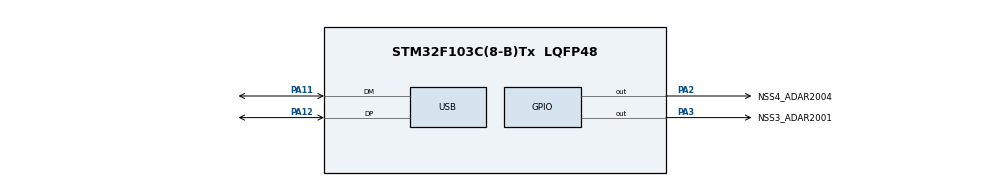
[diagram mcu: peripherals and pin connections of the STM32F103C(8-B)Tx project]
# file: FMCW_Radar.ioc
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Mcu.Family=STM32F1
Mcu.Name=STM32F103C(8-B)Tx
Mcu.Package=LQFP48
NVIC.PriorityGroup=NVIC_PRIORITYGROUP_4
NVIC.TIM3_IRQn=true\:0\:0\:false\:false\:true\:true\:true\:true
NVIC.TIM4_IRQn=true\:0\:0\:false\:false\:true\:true\:true\:true
PA11.Mode=Device
PA11.Signal=USB_DM
PA12.Mode=Device
PA12.Signal=USB_DP
PA13.Mode=Serial_Wire
PA13.Signal=SYS_JTMS-SWDIO
PA14.Mode=Serial_Wire
PA14.Signal=SYS_JTCK-SWCLK
PA2.GPIO_Label=NSS4_ADAR2004
PA2.GPIO_ModeDefaultOutputPP=GPIO_MODE_OUTPUT_OD
PA2.GPIO_PuPd=GPIO_NOPULL
PA2.GPIO_Speed=GPIO_SPEED_FREQ_HIGH
PA2.PinState=GPIO_PIN_SET
PA2.Signal=GPIO_Output
PA3.GPIO_Label=NSS3_ADAR2001
PA3.GPIO_ModeDefaultOutputPP=GPIO_MODE_OUTPUT_OD
PA3.GPIO_PuPd=GPIO_NOPULL
PA3.GPIO_Speed=GPIO_SPEED_FREQ_HIGH
PA3.PinState=GPIO_PIN_SET
PA3.Signal=GPIO_Output
PA4.GPIO_Label=NSS_ADF4372
PA4.GPIO_ModeDefaultOutputPP=GPIO_MO

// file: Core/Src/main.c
/* USER CODE BEGIN Header */
/**
  ******************************************************************************
  * @file           : main.c
  * @brief          : Main program body
  ******************************************************************************
  * @attention
  *
  * Copyright (c) 2026 STMicroelectronics.
  * All rights reserved.
  *
  * This software is licensed under terms that can be found in the LICENSE file
  * in the root directory of this software component.
  * If no LICENSE file comes with this software, it is provided AS-IS.
  *
  ******************************************************************************
  */
/* USER CODE END Header */
#include "main.h"

/* USER CODE BEGIN Includes */
#include "adar2001.h"
#include "adar2004.h"
#include "adf4372.h"
#include "dac7563.h"
#include <stdint.h>
/* USER CODE END Includes */

/* USER CODE BEGIN PTD */
//uint16_t test_dac_value = 4000;
/* USER CODE END PTD */

SPI_HandleTypeDef hspi1;
SPI_HandleTypeDef hspi2;

TIM_HandleTypeDef htim3;
TIM_HandleTypeDef htim4;

PCD_HandleTypeDef hpcd_USB_FS;

/* USER CODE BEGIN PV */
uint16_t dac_value = DAC_MIN_CODE;
uint16_t dac_increment = (DAC_MAX_CODE - DAC_MIN_CODE) / CHIRP_STEPS; // 2
volatile uint8_t dac_update_flag = 0;
volatile uint8_t dac_reset_flag = 0;
volatile uint8_t start_chirp_flag = 0;
uint8_t chirp_active = 0;
uint32_t chirp_step_count = 0;
uint32_t idle_count = 0;

volatile uint32_t reset_count = 0;   // debug counter
volatile uint32_t update_count = 0;  // debug counter
/* USER CODE END PV */

void SystemClock_Config(void);
static void MX_GPIO_Init(void);
static void MX_USB_PCD_Init(void);
static void MX_SPI2_Init(void);
static void MX_SPI1_Init(void);
static void MX_TIM3_Init(void);
static void MX_TIM4_Init(void);

int main(void)
{

  /* MCU Configuration--------------------------------------------------------*/

  /* Reset of all peripherals, Initializes the Flash interface and the Systick. */
  HAL_Init();

  /* Configure the system clock */
  SystemClock_Config();

  /* Initialize all configured peripherals */
  MX_GPIO_Init();
  MX_USB_PCD_Init();
  MX_SPI2_Init();
  MX_SPI1_Init();
  MX_TIM3_Init();
  MX_TIM4_Init();
  /* USER CODE BEGIN 2 */
  DAC7563_Init(&hspi2);
  ADF4372_Init(&hspi1);
  ADAR2001_Init(&hspi1);
  ADAR2004_Init(&hspi1);

  // Start Idle timer - chirp timer started by TIM4 callback
  HAL_TIM_Base_Start_IT(&htim4);
  /* USER CODE END 2 */

  /* Infinite loop */
  /* USER CODE BEGIN WHILE */
  while (1)
  {
      if (dac_reset_flag)
      {
          dac_reset_flag = 0;
          dac_update_flag = 0;
          reset_count++;  // increment every time reset fires
          DAC7563_Write(&hspi2, DAC_WRITE_UPDATE_A, DAC_MIN_CODE);
      }
      else if (dac_update_flag)
      {
          dac_update_flag = 0;
          update_count++;  // increment every time update fires
          DAC7563_Write(&hspi2, DAC_WRITE_UPDATE_A, dac_value);
      }

      if (start_chirp_flag)
      {
          start_chirp_flag = 0;
          dac_value = DAC_MIN_CODE;
          HAL_TIM_Base_Start_IT(&htim3);
      }
  }
  /* USER CODE END WHILE */

}

void SystemClock_Config(void)
{
  RCC_OscInitTypeDef RCC_OscInitStruct = {0};
  RCC_ClkInitTypeDef RCC_ClkInitStruct = {0};
  RCC_PeriphCLKInitTypeDef PeriphClkInit = {0};

  /** Initializes the RCC Oscillators according to the specified parameters
  * in the RCC_OscInitTypeDef structure.
  */
  RCC_OscInitStruct.OscillatorType = RCC_OSCILLATORTYPE_HSE;
  RCC_OscInitStruct.HSEState = RCC_HSE_ON;
  RCC_OscInitStruct.HSEPredivValue = RCC_HSE_PREDIV_DIV1;
  RCC_OscInitStruct.HSIState = RCC_HSI_ON;
  RCC_OscInitStruct.PLL.PLLState = RCC_PLL_ON;
  RCC_OscInitStruct.PLL.PLLSource = RCC_PLLSOURCE_HSE;
  RCC_OscInitStruct.PLL.PLLMUL = RCC_PLL_MUL6;
  if (HAL_RCC_OscConfig(&RCC_OscInitStruct) != HAL_OK)
  {
    Error_Handler();
  }

  /** Initializes the CPU, AHB and APB buses clocks
  */
  RCC_ClkInitStruct.ClockType = RCC_CLOCKTYPE_HCLK|RCC_CLOCKTYPE_SYSCLK
                              |RCC_CLOCKTYPE_PCLK1|RCC_CLOCKTYPE_PCLK2;
  RCC_ClkInitStruct.SYSCLKSource = RCC_SYSCLKSOURCE_PLLCLK;
  RCC_ClkInitStruct.AHBCLKDivider = RCC_SYSCLK_DIV1;
  RCC_ClkInitStruct.APB1CLKDivider = RCC_HCLK_DIV2;
  RCC_ClkInitStruct.APB2CLKDivider = RCC_HCLK_DIV1;

  if (HAL_RCC_ClockConfig(&RCC_ClkInitStruct, FLASH_LATENCY_1) != HAL_OK)
  {
    Error_Handler();
  }
  PeriphClkInit.PeriphClockSelection = RCC_PERIPHCLK_USB;
  PeriphClkInit.UsbClockSelection = RCC_USBCLKSOURCE_PLL;
  if (HAL_RCCEx_PeriphCLKConfig(&PeriphClkInit) != HAL_OK)
  {
    Error_Handler();
  }
}

static void MX_SPI1_Init(void)
{

  /* SPI1 parameter configuration*/
  hspi1.Instance = SPI1;
  hspi1.Init.Mode = SPI_MODE_MASTER;
  hspi1.Init.Direction = SPI_DIRECTION_2LINES;
  hspi1.Init.DataSize = SPI_DATASIZE_8BIT;
  hspi1.Init.CLKPolarity = SPI_POLARITY_LOW;
  hspi1.Init.CLKPhase = SPI_PHASE_1EDGE;
  hspi1.Init.NSS = SPI_NSS_SOFT;
  hspi1.Init.BaudRatePrescaler = SPI_BAUDRATEPRESCALER_4;
  hspi1.Init.FirstBit = SPI_FIRSTBIT_MSB;
  hspi1.Init.TIMode = SPI_TIMODE_DISABLE;
  hspi1.Init.CRCCalculation = SPI_CRCCALCULATION_DISABLE;
  hspi1.Init.CRCPolynomial = 10;
  if (HAL_SPI_Init(&hspi1) != HAL_OK)
  {
    Error_Handler();
  }

}

static void MX_SPI2_Init(void)
{

  /* SPI2 parameter configuration*/
  hspi2.Instance = SPI2;
  hspi2.Init.Mode = SPI_MODE_MASTER;
  hspi2.Init.Direction = SPI_DIRECTION_2LINES;
  hspi2.Init.DataSize = SPI_DATASIZE_8BIT;
  hspi2.Init.CLKPolarity = SPI_POLARITY_LOW;
  hspi2.Init.CLKPhase = SPI_PHASE_2EDGE;
  hspi2.Init.NSS = SPI_NSS_SOFT;
  hspi2.Init.BaudRatePrescaler = SPI_BAUDRATEPRESCALER_64;
  hspi2.Init.FirstBit = SPI_FIRSTBIT_MSB;
  hspi2.Init.TIMode = SPI_TIMODE_DISABLE;
  hspi2.Init.CRCCalculation = SPI_CRCCALCULATION_DISABLE;
  hspi2.Init.CRCPolynomial = 10;
  if (HAL_SPI_Init(&hspi2) != HAL_OK)
  {
    Error_Handler();
  }

}

static void MX_TIM3_Init(void)
{

  TIM_ClockConfigTypeDef sClockSourceConfig = {0};
  TIM_MasterConfigTypeDef sMasterConfig = {0};

  htim3.Instance = TIM3;
  htim3.Init.Prescaler = 47;
  htim3.Init.CounterMode = TIM_COUNTERMODE_UP;
  htim3.Init.Period = 127;
  htim3.Init.ClockDivision = TIM_CLOCKDIVISION_DIV1;
  htim3.Init.AutoReloadPreload = TIM_AUTORELOAD_PRELOAD_ENABLE;
  if (HAL_TIM_Base_Init(&htim3) != HAL_OK)
  {
    Error_Handler();
  }
  sClockSourceConfig.ClockSource = TIM_CLOCKSOURCE_INTERNAL;
  if (HAL_TIM_ConfigClockSource(&htim3, &sClockSourceConfig) != HAL_OK)
  {
    Error_Handler();
  }
  sMasterConfig.MasterOutputTrigger = TIM_TRGO_UPDATE;
  sMasterConfig.MasterSlaveMode = TIM_MASTERSLAVEMODE_DISABLE;
  if (HAL_TIMEx_MasterConfigSynchronization(&htim3, &sMasterConfig) != HAL_OK)
  {
    Error_Handler();
  }

}

static void MX_TIM4_Init(void)
{

  TIM_ClockConfigTypeDef sClockSourceConfig = {0};
  TIM_MasterConfigTypeDef sMasterConfig = {0};

  htim4.Instance = TIM4;
  htim4.Init.Prescaler = 23999;
  htim4.Init.CounterMode = TIM_COUNTERMODE_UP;
  htim4.Init.Period = 15;
  htim4.Init.ClockDivision = TIM_CLOCKDIVISION_DIV1;
  htim4.Init.AutoReloadPreload = TIM_AUTORELOAD_PRELOAD_DISABLE;
  if (HAL_TIM_Base_Init(&htim4) != HAL_OK)
  {
    Error_Handler();
  }
  sClockSourceConfig.ClockSource = TIM_CLOCKSOURCE_INTERNAL;
  if (HAL_TIM_ConfigClockSource(&htim4, &sClockSourceConfig) != HAL_OK)
  {
    Error_Handler();
  }
  sMasterConfig.MasterOutputTrigger = TIM_TRGO_RESET;
  sMasterConfig.MasterSlaveMode = TIM_MASTERSLAVEMODE_DISABLE;
  if (HAL_TIMEx_MasterConfigSynchronization(&htim4, &sMasterConfig) != HAL_OK)
  {
    Error_Handler();
  }

}

static void MX_USB_PCD_Init(void)
{

  hpcd_USB_FS.Instance = USB;
  hpcd_USB_FS.Init.dev_endpoints = 8;
  hpcd_USB_FS.Init.speed = PCD_SPEED_FULL;
  hpcd_USB_FS.Init.low_power_enable = DISABLE;
  hpcd_USB_FS.Init.lpm_enable = DISABLE;
  hpcd_USB_FS.Init.battery_charging_enable = DISABLE;
  if (HAL_PCD_Init(&hpcd_USB_FS) != HAL_OK)
  {
    Error_Handler();
  }

}

static void MX_GPIO_Init(void)
{
  GPIO_InitTypeDef GPIO_InitStruct = {0};

  /* GPIO Ports Clock Enable */
  __HAL_RCC_GPIOD_CLK_ENABLE();
  __HAL_RCC_GPIOA_CLK_ENABLE();
  __HAL_RCC_GPIOB_CLK_ENABLE();

  /*Configure GPIO pin Output Level */
  HAL_GPIO_WritePin(GPIOA, NSS4_ADAR2004_Pin|NSS3_ADAR2001_Pin|NSS_ADF4372_Pin, GPIO_PIN_SET);

  /*Configure GPIO pin Output Level */
  HAL_GPIO_WritePin(GPIOB, DAC_NCLR_Pin|DAC_NLDAC_Pin|NSS_DAC7563_Pin, GPIO_PIN_SET);

  /*Configure GPIO pins : NSS4_ADAR2004_Pin NSS3_ADAR2001_Pin NSS_ADF4372_Pin */
  GPIO_InitStruct.Pin = NSS4_ADAR2004_Pin|NSS3_ADAR2001_Pin|NSS_ADF4372_Pin;
  GPIO_InitStruct.Mode = GPIO_MODE_OUTPUT_OD;
  GPIO_InitStruct.Pull = GPIO_NOPULL;
  GPIO_InitStruct.Speed = GPIO_SPEED_FREQ_HIGH;
  HAL_GPIO_Init(GPIOA, &GPIO_InitStruct);

  /*Configure GPIO pins : DAC_NCLR_Pin DAC_NLDAC_Pin */
  GPIO_InitStruct.Pin = DAC_NCLR_Pin|DAC_NLDAC_Pin;
  GPIO_InitStruct.Mode = GPIO_MODE_OUTPUT_PP;
  GPIO_InitStruct.Pull = GPIO_NOPULL;
  GPIO_InitStruct.Speed = GPIO_SPEED_FREQ_LOW;
  HAL_GPIO_Init(GPIOB, &GPIO_InitStruct);

  /*Configure GPIO pin : NSS_DAC7563_Pin */
  GPIO_InitStruct.Pin = NSS_DAC7563_Pin;
  GPIO_InitStruct.Mode = GPIO_MODE_OUTPUT_PP;
  GPIO_InitStruct.Pull = GPIO_NOPULL;
  GPIO_InitStruct.Speed = GPIO_SPEED_FREQ_MEDIUM;
  HAL_GPIO_Init(NSS_DAC7563_GPIO_Port, &GPIO_InitStruct);

}

/* USER CODE BEGIN 4 */
void HAL_TIM_PeriodElapsedCallback(TIM_HandleTypeDef *htim)
{
    if (htim->Instance == TIM3)
    {
        if (dac_value >= DAC_MAX_CODE)
        {
            dac_update_flag = 0;
            dac_reset_flag = 1;
            dac_value = DAC_MIN_CODE;
            HAL_TIM_Base_Stop_IT(&htim3);
            HAL_TIM_Base_Start_IT(&htim4);
        }
        else
        {
            dac_value += dac_increment;
            dac_update_flag = 1;
        }
    }

    if (htim->Instance == TIM4)
    {
        HAL_TIM_Base_Stop_IT(&htim4);
        start_chirp_flag = 1;  // Signal main loop to start chirp
    }
}
/* USER CODE END 4 */

void Error_Handler(void)
{
  __disable_irq();
  while (1)
  {
  }
}
